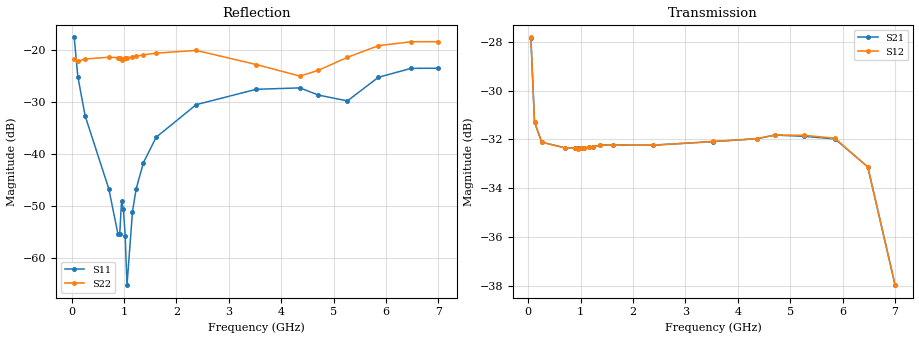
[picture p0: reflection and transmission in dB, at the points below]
! Integrated Device Technology
! Corporate Headquarters
! 6024 Silver Creek Valley Road
! San Jose, CA 95138  USA
! Phone:  1-408-284-8200
! Toll Free:  1-800-223-1366
! Webpage:  http://www.idt.com/
! Timing and RF Division
! 515 Groton Road, Suite 102
! Westford, MA 01886-6024
! Device:  F2258
! Description: Voltage Variable RF Attenuator
! Frequency:  50.0 -  6000.00 MHz
! Package:  3x3 mm Thin QFN Plastic Package: 16 pin
! Ports:  2 RF, 2 DC
!  Pin  1  = NC
!  Pin  2  = NC
!  Pin  3  = RF2  = Port 2
!  Pin  4  = GND
!  Pin  5  = Vdd
!  Pin  6  = NC
!  Pin  7  = VCTRL
!  Pin  8  = NC
!  Pin  9  = GND
!  Pin 10  = RF1  = Port 1
!  Pin 11  = NC
!  Pin 12  = NC
!  Pin 13  = NC
!  Pin 14  = NC
!  Pin 15  = NC
!  Pin 16  = NC
! Vcntrl:  1.750 Volts
! Vdd:  +3.300 Volts
! Current:  1.158 mA
! Data:  The device was measured on a the F2258 evaluation board which has
!  individual transmission lines to the RF pins.  Data was collected
!  using a calibrated network analyzer.  The evaluation board was
!  de-embedded using a TRL calibration technique.
!  The reference plane is the edge of the package pin.
! Misc:  SN 10
!  Action Tracker AT0285
! Date Measured:  2014-12-10
! Date:  2016-01-13  MJV
! Note:
!  Integrated Device Technology supplies this data as a sample of measured
!  data at the package pin for this product.  Your particular data for this
!  product may vary.
!  Data was taken at 25 degrees C.
!  Integrated Device Technology reserves the right to change this data at anytime.
!Freq_(GHz)  S11M_(dB)  S11P_(deg)  S21M_(dB)  S21P_(deg)  S12M_(dB)  S12P_(deg)  S22M_(dB)  S22P_(deg)
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# GHz S dB R 50
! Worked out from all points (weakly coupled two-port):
!   201 points, 50 MHz to 7 GHz, reference 50 ohm
!   highest |S21| = -27.84 dB at 50 MHz (marker M1); lowest = -37.9 dB at 7 GHz (marker M2)
!   lowest |S11| = -65.3 dB at 1.058 GHz (marker M3), VSWR 1.00, Z = 50 + j0.0353 ohm
!   |S11| at or under -10 dB: start of sweep to end of sweep
!   |S22| runs from -25.0 to -18.3 dB; largest |S21 - S12| = 0.00013
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0.05  -17.53 -110.4  -27.84 -56.6  -27.83 -56.6  -21.65 -72.7
0.1195  -25.10 -105.9  -31.30 -29.9  -31.29 -29.9  -22.14 -24.3
0.2585  -32.65 -109.8  -32.11 -16.0  -32.12 -16.0  -21.70 -11.1
0.71025  -46.71 -128.6  -32.35 -10.0  -32.34 -10.0  -21.35 -7.3
0.884  -55.39 167.4  -32.34 -10.1  -32.35 -10.0  -21.44 -9.0
0.91875  -55.39 144.4  -32.33 -10.1  -32.36 -10.1  -21.48 -9.3
0.9535  -49.07 -156.0  -32.36 -10.1  -32.38 -10.1  -21.80 -8.2
0.98825  -50.56 -168.0  -32.34 -10.2  -32.33 -10.2  -21.68 -9.0
1.023  -55.82 -179.7  -32.33 -10.3  -32.33 -10.3  -21.55 -9.4
1.05775  -65.26 139.6  -32.34 -10.3  -32.34 -10.3  -21.52 -9.3
1.162  -51.11 54.1  -32.32 -10.6  -32.30 -10.6  -21.29 -10.1
1.2315  -46.74 36.8  -32.30 -10.9  -32.29 -10.9  -21.16 -10.5
1.3705  -41.68 32.4  -32.24 -11.8  -32.23 -11.8  -20.90 -11.2
1.61375  -36.77 30.2  -32.23 -13.5  -32.22 -13.5  -20.57 -13.1
2.37825  -30.49 46.6  -32.23 -18.6  -32.24 -18.6  -20.04 -16.7
3.525  -27.53 90.9  -32.09 -27.2  -32.08 -27.2  -22.76 -25.0
4.359  -27.26 104.5  -31.97 -34.4  -31.97 -34.4  -24.99 -41.8
4.7065  -28.64 95.2  -31.82 -37.7  -31.82 -37.7  -23.88 -48.3
5.2625  -29.77 53.2  -31.87 -43.8  -31.83 -43.9  -21.38 -51.2
5.85325  -25.22 29.1  -31.98 -53.3  -31.95 -53.3  -19.13 -50.9
6.47875  -23.50 40.9  -33.12 -67.8  -33.13 -67.8  -18.37 -69.1
7  -23.47 84.1  -37.95 -68.0  -37.95 -67.9  -18.35 -123.5
